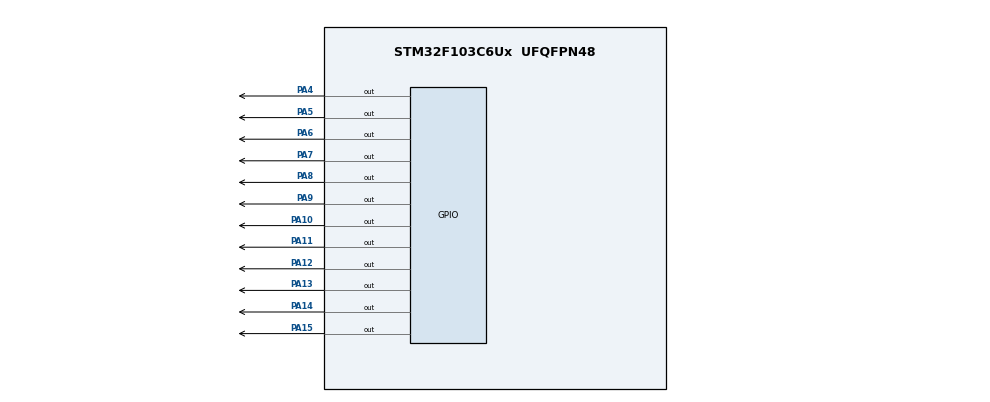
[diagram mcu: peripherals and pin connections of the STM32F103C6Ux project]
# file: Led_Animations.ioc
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Mcu.Family=STM32F1
Mcu.Name=STM32F103C6Ux
Mcu.Package=UFQFPN48
NVIC.PriorityGroup=NVIC_PRIORITYGROUP_4
PA10.Signal=GPIO_Output
PA11.Signal=GPIO_Output
PA12.Signal=GPIO_Output
PA13.Signal=GPIO_Output
PA14.Signal=GPIO_Output
PA15.Signal=GPIO_Output
PA4.Signal=GPIO_Output
PA5.Signal=GPIO_Output
PA6.Signal=GPIO_Output
PA7.Signal=GPIO_Output
PA8.Signal=GPIO_Output
PA9.Signal=GPIO_Output
ProjectManager.HeapSize=0x200
ProjectManager.StackSize=0x400
ProjectManager.TargetToolchain=STM32CubeIDE
RCC.APB1Freq_Value=8000000
RCC.APB2Freq_Value=8000000
VP_SYS_VS_ND.Mode=No_Debug
board=custom

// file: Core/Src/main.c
/* USER CODE BEGIN Header */
/**
  ******************************************************************************
  * @file           : main.c
  * @brief          : Main program body
  ******************************************************************************
  * @attention
  *
  * <h2><center>&copy; Copyright (c) 2023 STMicroelectronics.
  * All rights reserved.</center></h2>
  *
  * This software component is licensed by ST under BSD 3-Clause license,
  * the "License"; You may not use this file except in compliance with the
  * License. You may obtain a copy of the License at:
  *                        opensource.org/licenses/BSD-3-Clause
  *
  ******************************************************************************
  */
/* USER CODE END Header */
#include "main.h"

void SystemClock_Config(void);
static void MX_GPIO_Init(void);
/* USER CODE BEGIN PFP */
void display7SEG(int num);
/* USER CODE END PFP */

int main(void)
{

  /* MCU Configuration--------------------------------------------------------*/

  /* Reset of all peripherals, Initializes the Flash interface and the Systick. */
  HAL_Init();

  /* Configure the system clock */
  SystemClock_Config();

  /* Initialize all configured peripherals */
  MX_GPIO_Init();
  /* USER CODE BEGIN 2 */
  enum Color {
	  RED1_GREEN2, RED1_YELLOW2,
	  GREEN1_RED2, YELLOW1_RED2
  };

  int counter = 0;
  int counter1 = 5;
  int counter2 = 3;
  enum Color state = RED1_GREEN2;

  // RESET STATE
  HAL_GPIO_WritePin(GPIOA, LED_RED_1_Pin|LED_GREEN_2_Pin, GPIO_PIN_RESET);
  HAL_GPIO_WritePin(GPIOA, LED_YELLOW_1_Pin|LED_GREEN_1_Pin|LED_RED_2_Pin|LED_YELLOW_2_Pin, GPIO_PIN_SET);
  HAL_GPIO_WritePin(GPIOB, A_7SEG_Pin|B_7SEG_Pin|C_7SEG_Pin|D_7SEG_Pin|E_7SEG_Pin|F_7SEG_Pin|G_7SEG_Pin, GPIO_PIN_SET);
  /* USER CODE END 2 */

  /* Infinite loop */
  /* USER CODE BEGIN WHILE */
  while (1)
  {
	  if(counter >= 10) counter = 0;
	  display7SEG(counter++);
	  switch (state) {
	  case RED1_GREEN2:
		  if(counter2 <= 0) {
			  // 1
			  // DO NOTHING
			  // 2
			  HAL_GPIO_WritePin(LED_GREEN_2_GPIO_Port, LED_GREEN_2_Pin, GPIO_PIN_SET);
			  HAL_GPIO_WritePin(LED_YELLOW_2_GPIO_Port, LED_YELLOW_2_Pin, GPIO_PIN_RESET);
			  state = RED1_YELLOW2;
			  counter2 = 2;
		  }
		  break;
	  case RED1_YELLOW2:
		  if(counter2 <= 0) {
			  // 1
			  HAL_GPIO_WritePin(LED_RED_1_GPIO_Port, LED_RED_1_Pin, GPIO_PIN_SET);
			  HAL_GPIO_WritePin(LED_GREEN_1_GPIO_Port, LED_GREEN_1_Pin, GPIO_PIN_RESET);
			  counter1 = 3;
			  // 2
			  HAL_GPIO_WritePin(LED_YELLOW_2_GPIO_Port, LED_YELLOW_2_Pin, GPIO_PIN_SET);
			  HAL_GPIO_WritePin(LED_RED_2_GPIO_Port, LED_RED_2_Pin, GPIO_PIN_RESET);
			  state = GREEN1_RED2;
			  counter2 = 5;
		  }
		  break;
	  case GREEN1_RED2:
		  if(counter1 <= 0) {
			  // 1
			  HAL_GPIO_WritePin(LED_GREEN_1_GPIO_Port, LED_GREEN_1_Pin, GPIO_PIN_SET);
			  HAL_GPIO_WritePin(LED_YELLOW_1_GPIO_Port, LED_YELLOW_1_Pin, GPIO_PIN_RESET);
			  state = YELLOW1_RED2;
			  counter1 = 2;
			  // 2
			  // DO NOTHING
		  }
	  case YELLOW1_RED2:
		  if(counter1 <= 0) {
			  // 1
			  HAL_GPIO_WritePin(LED_YELLOW_1_GPIO_Port, LED_YELLOW_1_Pin, GPIO_PIN_SET);
			  HAL_GPIO_WritePin(LED_RED_1_GPIO_Port, LED_RED_1_Pin, GPIO_PIN_RESET);
			  counter1 = 5;
			  // 2
			  HAL_GPIO_WritePin(LED_RED_2_GPIO_Port, LED_RED_2_Pin, GPIO_PIN_SET);
			  HAL_GPIO_WritePin(LED_GREEN_2_GPIO_Port, LED_GREEN_2_Pin, GPIO_PIN_RESET);
			  state = RED1_GREEN2;
			  counter2 = 3;
		  }
		  break;
	  default:
		  break;
	  }
	  counter1 = counter1 - 1;
	  counter2 = counter2 - 1;
	  HAL_Delay(1000);
    /* USER CODE END WHILE */

  }
}

void SystemClock_Config(void)
{
  RCC_OscInitTypeDef RCC_OscInitStruct = {0};
  RCC_ClkInitTypeDef RCC_ClkInitStruct = {0};

  /** Initializes the RCC Oscillators according to the specified parameters
  * in the RCC_OscInitTypeDef structure.
  */
  RCC_OscInitStruct.OscillatorType = RCC_OSCILLATORTYPE_HSI;
  RCC_OscInitStruct.HSIState = RCC_HSI_ON;
  RCC_OscInitStruct.HSICalibrationValue = RCC_HSICALIBRATION_DEFAULT;
  RCC_OscInitStruct.PLL.PLLState = RCC_PLL_NONE;
  if (HAL_RCC_OscConfig(&RCC_OscInitStruct) != HAL_OK)
  {
    Error_Handler();
  }
  /** Initializes the CPU, AHB and APB buses clocks
  */
  RCC_ClkInitStruct.ClockType = RCC_CLOCKTYPE_HCLK|RCC_CLOCKTYPE_SYSCLK
                              |RCC_CLOCKTYPE_PCLK1|RCC_CLOCKTYPE_PCLK2;
  RCC_ClkInitStruct.SYSCLKSource = RCC_SYSCLKSOURCE_HSI;
  RCC_ClkInitStruct.AHBCLKDivider = RCC_SYSCLK_DIV1;
  RCC_ClkInitStruct.APB1CLKDivider = RCC_HCLK_DIV1;
  RCC_ClkInitStruct.APB2CLKDivider = RCC_HCLK_DIV1;

  if (HAL_RCC_ClockConfig(&RCC_ClkInitStruct, FLASH_LATENCY_0) != HAL_OK)
  {
    Error_Handler();
  }
}

static void MX_GPIO_Init(void)
{
  GPIO_InitTypeDef GPIO_InitStruct = {0};

  /* GPIO Ports Clock Enable */
  __HAL_RCC_GPIOA_CLK_ENABLE();
  __HAL_RCC_GPIOB_CLK_ENABLE();

  /*Configure GPIO pin Output Level */
  HAL_GPIO_WritePin(GPIOA, LED_RED_1_Pin|LED_YELLOW_1_Pin|LED_GREEN_1_Pin|LED_RED_2_Pin
                          |LED_YELLOW_2_Pin|LED_GREEN_2_Pin, GPIO_PIN_RESET);

  /*Configure GPIO pin Output Level */
  HAL_GPIO_WritePin(GPIOB, A_7SEG_Pin|B_7SEG_Pin|C_7SEG_Pin|D_7SEG_Pin
                          |E_7SEG_Pin|F_7SEG_Pin|G_7SEG_Pin, GPIO_PIN_RESET);

  /*Configure GPIO pins : LED_RED_1_Pin LED_YELLOW_1_Pin LED_GREEN_1_Pin LED_RED_2_Pin
                           LED_YELLOW_2_Pin LED_GREEN_2_Pin */
  GPIO_InitStruct.Pin = LED_RED_1_Pin|LED_YELLOW_1_Pin|LED_GREEN_1_Pin|LED_RED_2_Pin
                          |LED_YELLOW_2_Pin|LED_GREEN_2_Pin;
  GPIO_InitStruct.Mode = GPIO_MODE_OUTPUT_PP;
  GPIO_InitStruct.Pull = GPIO_NOPULL;
  GPIO_InitStruct.Speed = GPIO_SPEED_FREQ_LOW;
  HAL_GPIO_Init(GPIOA, &GPIO_InitStruct);

  /*Configure GPIO pins : A_7SEG_Pin B_7SEG_Pin C_7SEG_Pin D_7SEG_Pin
                           E_7SEG_Pin F_7SEG_Pin G_7SEG_Pin */
  GPIO_InitStruct.Pin = A_7SEG_Pin|B_7SEG_Pin|C_7SEG_Pin|D_7SEG_Pin
                          |E_7SEG_Pin|F_7SEG_Pin|G_7SEG_Pin;
  GPIO_InitStruct.Mode = GPIO_MODE_OUTPUT_PP;
  GPIO_InitStruct.Pull = GPIO_NOPULL;
  GPIO_InitStruct.Speed = GPIO_SPEED_FREQ_LOW;
  HAL_GPIO_Init(GPIOB, &GPIO_InitStruct);

}

/* USER CODE BEGIN 4 */
void display7SEG(int num) {
	switch (num) {
	case 0:
		HAL_GPIO_WritePin(GPIOB, G_7SEG_Pin, GPIO_PIN_SET);
		HAL_GPIO_WritePin(GPIOB, A_7SEG_Pin|B_7SEG_Pin|C_7SEG_Pin|D_7SEG_Pin|E_7SEG_Pin|F_7SEG_Pin, GPIO_PIN_RESET);
		break;
	case 1:
		HAL_GPIO_WritePin(GPIOB, A_7SEG_Pin|D_7SEG_Pin|E_7SEG_Pin|F_7SEG_Pin|G_7SEG_Pin, GPIO_PIN_SET);
		HAL_GPIO_WritePin(GPIOB, B_7SEG_Pin|C_7SEG_Pin, GPIO_PIN_RESET);
		break;
	case 2:
		HAL_GPIO_WritePin(GPIOB, C_7SEG_Pin|F_7SEG_Pin, GPIO_PIN_SET);
		HAL_GPIO_WritePin(GPIOB, A_7SEG_Pin|B_7SEG_Pin|D_7SEG_Pin|E_7SEG_Pin|G_7SEG_Pin, GPIO_PIN_RESET);
		break;
	case 3:
		HAL_GPIO_WritePin(GPIOB, E_7SEG_Pin|F_7SEG_Pin, GPIO_PIN_SET);
		HAL_GPIO_WritePin(GPIOB, A_7SEG_Pin|B_7SEG_Pin|C_7SEG_Pin|D_7SEG_Pin|G_7SEG_Pin, GPIO_PIN_RESET);
		break;
	case 4:
		HAL_GPIO_WritePin(GPIOB, A_7SEG_Pin|D_7SEG_Pin|E_7SEG_Pin, GPIO_PIN_SET);
		HAL_GPIO_WritePin(GPIOB, B_7SEG_Pin|C_7SEG_Pin|F_7SEG_Pin|G_7SEG_Pin, GPIO_PIN_RESET);
		break;
	case 5:
		HAL_GPIO_WritePin(GPIOB, B_7SEG_Pin|E_7SEG_Pin, GPIO_PIN_SET);
		HAL_GPIO_WritePin(GPIOB, A_7SEG_Pin|C_7SEG_Pin|D_7SEG_Pin|F_7SEG_Pin|G_7SEG_Pin, GPIO_PIN_RESET);
		break;
	case 6:
		HAL_GPIO_WritePin(GPIOB, B_7SEG_Pin, GPIO_PIN_SET);
		HAL_GPIO_WritePin(GPIOB, A_7SEG_Pin|C_7SEG_Pin|D_7SEG_Pin|E_7SEG_Pin|F_7SEG_Pin|G_7SEG_Pin, GPIO_PIN_RESET);
		break;
	case 7:
		HAL_GPIO_WritePin(GPIOB, D_7SEG_Pin|E_7SEG_Pin|F_7SEG_Pin|G_7SEG_Pin, GPIO_PIN_SET);
		HAL_GPIO_WritePin(GPIOB, A_7SEG_Pin|B_7SEG_Pin|C_7SEG_Pin, GPIO_PIN_RESET);
		break;
	case 8:
		HAL_GPIO_WritePin(GPIOB, A_7SEG_Pin|B_7SEG_Pin|C_7SEG_Pin|D_7SEG_Pin|E_7SEG_Pin|F_7SEG_Pin|G_7SEG_Pin, GPIO_PIN_RESET);
		break;
	case 9:
		HAL_GPIO_WritePin(GPIOB, E_7SEG_Pin, GPIO_PIN_SET);
		HAL_GPIO_WritePin(GPIOB, A_7SEG_Pin|B_7SEG_Pin|C_7SEG_Pin|D_7SEG_Pin|F_7SEG_Pin|G_7SEG_Pin, GPIO_PIN_RESET);
		break;
	default:
		HAL_GPIO_WritePin(GPIOB, A_7SEG_Pin|B_7SEG_Pin|C_7SEG_Pin|D_7SEG_Pin|E_7SEG_Pin|F_7SEG_Pin|G_7SEG_Pin, GPIO_PIN_SET);
		break;
	}
}
/* USER CODE END 4 */

void Error_Handler(void)
{
  __disable_irq();
  while (1)
  {
  }
}

/************************ (C) COPYRIGHT STMicroelectronics *****END OF FILE****/
